# Synthetic scalar technology for native geometry regression, not foundry qualification.
VERSION 5.8 ;
UNITS
  DATABASE MICRONS 2000 ;
END UNITS
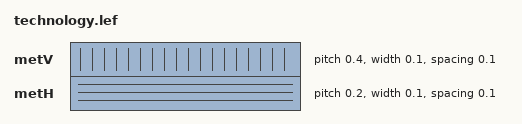
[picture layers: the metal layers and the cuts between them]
LAYER metH
  TYPE ROUTING ;
  DIRECTION HORIZONTAL ;
  PITCH 0.2 ;
  OFFSET 0.1 ;
  WIDTH 0.1 ;
  SPACING 0.1 ;
END metH
LAYER metV
  TYPE ROUTING ;
  DIRECTION VERTICAL ;
  PITCH 0.4 ;
  OFFSET 0.1 ;
  WIDTH 0.1 ;
  SPACING 0.1 ;
END metV
END LIBRARY
